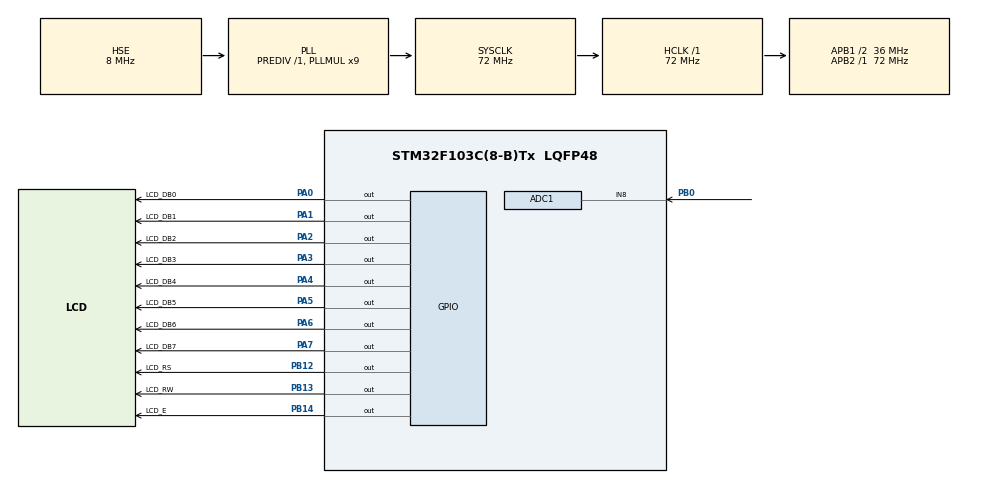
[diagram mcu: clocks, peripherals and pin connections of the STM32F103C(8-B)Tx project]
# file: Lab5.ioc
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ADC1.Channel-0\#ChannelRegularConversion=ADC_CHANNEL_8
ADC1.ContinuousConvMode=ENABLE
ADC1.NbrOfConversionFlag=1
ADC1.Rank-0\#ChannelRegularConversion=1
ADC1.SamplingTime-0\#ChannelRegularConversion=ADC_SAMPLETIME_1CYCLE_5
ADC1.master=1
Mcu.Family=STM32F1
Mcu.Name=STM32F103C(8-B)Tx
Mcu.Package=LQFP48
NVIC.PriorityGroup=NVIC_PRIORITYGROUP_4
PA0-WKUP.GPIO_Label=LCD_DB0
PA0-WKUP.GPIO_Speed=GPIO_SPEED_FREQ_MEDIUM
PA0-WKUP.Signal=GPIO_Output
PA1.GPIO_Label=LCD_DB1
PA1.GPIO_Speed=GPIO_SPEED_FREQ_MEDIUM
PA1.Signal=GPIO_Output
PA13.Mode=Serial_Wire
PA13.Signal=SYS_JTMS-SWDIO
PA14.Mode=Serial_Wire
PA14.Signal=SYS_JTCK-SWCLK
PA2.GPIO_Label=LCD_DB2
PA2.GPIO_Speed=GPIO_SPEED_FREQ_MEDIUM
PA2.Signal=GPIO_Output
PA3.GPIO_Label=LCD_DB3
PA3.GPIO_Speed=GPIO_SPEED_FREQ_MEDIUM
PA3.Signal=GPIO_Output
PA4.GPIO_Label=LCD_DB4
PA4.GPIO_Speed=GPIO_SPEED_FREQ_MEDIUM
PA4.Signal=GPIO_Output
PA5.GPIO_Label=LCD_DB5
PA5.GPIO_Speed=GPIO_SPEED_FREQ_MEDIUM
PA5.Signal=GPIO_Output
PA6.GPIO_Label=LCD_DB6
PA6.GPIO_Speed=GPIO_SPEED_FREQ_MEDIUM
PA6.Signal=GPIO_Output
PA7.GPIO_Label=LCD_DB7
PA7.GPIO_Speed=GPIO_SPEED_FREQ_MEDIUM
PA7.Signal=GPIO_Output
PB0.Signal=ADCx_IN8
PB12.GPIO_Label=LCD_RS
PB12.GPIO_Speed=GPIO_SPEED_FREQ_MEDIUM
PB12.Signal=GPIO_Output
PB13.GPIO_Label=LCD_RW
PB13.GPIO_Speed=GPIO_SPEED_FREQ_MEDIUM
PB13.Signal=GPIO_Output
PB14.GPIO_Label=LCD_E
PB14.GPIO_Speed=GPIO_SPEED_FREQ_MEDIUM
PB14.Signal=GPIO_Output
PD0-OSC_IN.Mode=HSE-External-Oscillator
PD0-OSC_IN.Signal=RCC_OSC_IN
PD1-OSC_OUT.Mode=HSE-External-Oscillator
PD1-OSC_OUT.Signal=RCC_OSC_OUT
ProjectManager.HeapSize=0x200
ProjectManager.StackSize=0x400
ProjectManager.TargetToolchain=Makefile
RCC.ADCPresc=RCC_ADCPCLK2_DIV6
RCC.AHBFreq_Value=72000000
RCC.APB1CLKDivider=RCC_HCLK_DIV2
RCC.APB1Freq_Value=36000000
RCC.APB1TimFreq_Value=72000000
RCC.APB2Freq_Value=72000000
RCC.APB2TimFreq_Value=72000000
RCC.HCLKFreq_Value=72000000
RCC.PLLMUL=RCC_PLL_MUL9
RCC.PLLSourceVirtual=RCC_PLLSOURCE_HSE
RCC.SYSCLKFreq_VALUE=72000000
RCC.SYSCLKSource=RCC_SYSCLKSOURCE_PLLCLK
RCC.USBFreq_Value=72000000
SH.ADCx_IN8.0=ADC1_IN8,IN8
board=custom

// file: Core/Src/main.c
/* USER CODE BEGIN Header */
/**
 ******************************************************************************
 * @file           : main.c
 * @brief          : Main program body
 ******************************************************************************
 * @attention
 *
 * Copyright (c) 2024 STMicroelectronics.
 * All rights reserved.
 *
 * This software is licensed under terms that can be found in the LICENSE file
 * in the root directory of this software component.
 * If no LICENSE file comes with this software, it is provided AS-IS.
 *
 ******************************************************************************
 */
/* USER CODE END Header */
#include "adc.h"
#include "gpio.h"
#include "main.h"

/* USER CODE BEGIN Includes */
#include "Delay.h"
#include "lcd1602.h"
/* USER CODE END Includes */

void SystemClock_Config(void);

int main(void) {

  /* MCU Configuration--------------------------------------------------------*/

  /* Reset of all peripherals, Initializes the Flash interface and the Systick.
   */
  HAL_Init();

  /* Configure the system clock */
  SystemClock_Config();

  /* Initialize all configured peripherals */
  MX_GPIO_Init();
  MX_ADC1_Init();
  /* USER CODE BEGIN 2 */

  LCD_init(); // BJ LCD initiate
  // uchar startStr2[] = "SJTU JI - LAB3";
  uchar Str1[] = {"voltage:"};
  uchar Space = ' '; // LCD显示‘：’
  uchar dot = '.';   // LCD显示".";
  uchar unit = 'v';  // LCD显示"v";
  uchar Num0 = '0';  // LCD显示数字“0”

  uint16_t AD_Value; // 保存AD采样得到的值
  float voltage;     // 保存浮点
  uint8_t vol0;
  uint8_t vol1;
  uint8_t vol2;
  uint8_t volt0;
  uint8_t volt1;
  uint8_t volt2;

  /* USER CODE END 2 */

  /* Infinite loop */
  while (1) {

    /* USER CODE BEGIN 3 */

    HAL_ADC_Start(&hadc1); // 启动ADC转换
    HAL_ADC_PollForConversion(
        &hadc1, 10); // 等待转换完成，第二个参数表示超时时间，单位ms.
    if (HAL_IS_BIT_SET(HAL_ADC_GetState(&hadc1), HAL_ADC_STATE_REG_EOC)) {
      AD_Value = HAL_ADC_GetValue(&hadc1); // 读取ADC转换数据，数据为12位
    }

    voltage =
        (float)AD_Value / 4095 * 3.3; // 将AD值线性变换到0~3.3的范围，表示电压

    volt0 = (uchar)((int)(voltage * 100) % 100); // 小数后面两位
    volt1 = (uchar)(voltage * 10) % 10;          // 小数后面第一位
    volt2 = (uchar)(volt0) % 10;                 // 小数后面第二位

    /*以下LCD显示电压AD采样值*/
    LCD_Display_String(0, 0, Str1); // 显示"voltage:"
    LCD_Display_Char(unit, 13, 0);  // 显示”v"
    LCD_Display_Char(Space, 8, 0);  // 显示”：“
    LCD_Display_Char(dot, 10, 0);   // 显示“.”

    vol0 = Num0 + (int)voltage; // 模拟电压的整数部分值
    vol1 = Num0 + volt1; // 模拟电压的小数后面第一位
    vol2 = Num0 + volt2; // 模拟电压的小数后面第二位

    LCD_Display_Char(vol0, 9, 0); // 显示电压值的整数部分
    LCD_Display_Char(vol1, 11, 0); // 显示电压值的小数第一位部分
    LCD_Display_Char(vol2, 12, 0); // 显示电压值的小数第二位部分

    Delay_ms(100);
  }
  /* USER CODE END 3 */
}

void SystemClock_Config(void) {
  RCC_OscInitTypeDef RCC_OscInitStruct = {0};
  RCC_ClkInitTypeDef RCC_ClkInitStruct = {0};
  RCC_PeriphCLKInitTypeDef PeriphClkInit = {0};

  /** Initializes the RCC Oscillators according to the specified parameters
   * in the RCC_OscInitTypeDef structure.
   */
  RCC_OscInitStruct.OscillatorType = RCC_OSCILLATORTYPE_HSE;
  RCC_OscInitStruct.HSEState = RCC_HSE_ON;
  RCC_OscInitStruct.HSEPredivValue = RCC_HSE_PREDIV_DIV1;
  RCC_OscInitStruct.HSIState = RCC_HSI_ON;
  RCC_OscInitStruct.PLL.PLLState = RCC_PLL_ON;
  RCC_OscInitStruct.PLL.PLLSource = RCC_PLLSOURCE_HSE;
  RCC_OscInitStruct.PLL.PLLMUL = RCC_PLL_MUL9;
  if (HAL_RCC_OscConfig(&RCC_OscInitStruct) != HAL_OK) {
    Error_Handler();
  }

  /** Initializes the CPU, AHB and APB buses clocks
   */
  RCC_ClkInitStruct.ClockType = RCC_CLOCKTYPE_HCLK | RCC_CLOCKTYPE_SYSCLK |
                                RCC_CLOCKTYPE_PCLK1 | RCC_CLOCKTYPE_PCLK2;
  RCC_ClkInitStruct.SYSCLKSource = RCC_SYSCLKSOURCE_PLLCLK;
  RCC_ClkInitStruct.AHBCLKDivider = RCC_SYSCLK_DIV1;
  RCC_ClkInitStruct.APB1CLKDivider = RCC_HCLK_DIV2;
  RCC_ClkInitStruct.APB2CLKDivider = RCC_HCLK_DIV1;

  if (HAL_RCC_ClockConfig(&RCC_ClkInitStruct, FLASH_LATENCY_2) != HAL_OK) {
    Error_Handler();
  }
  PeriphClkInit.PeriphClockSelection = RCC_PERIPHCLK_ADC;
  PeriphClkInit.AdcClockSelection = RCC_ADCPCLK2_DIV6;
  if (HAL_RCCEx_PeriphCLKConfig(&PeriphClkInit) != HAL_OK) {
    Error_Handler();
  }
}

void Error_Handler(void) {
  __disable_irq();
  while (1) {
  }
}

#ifdef USE_FULL_ASSERT
/**
 * @brief  Reports the name of the source file and the source line number
 *         where the assert_param error has occurred.
 * @param  file: pointer to the source file name
 * @param  line: assert_param error line source number
 * @retval None
 */
void assert_failed(uint8_t *file, uint32_t line) {
  /* USER CODE BEGIN 6 */
  /* User can add his own implementation to report the file name and line
     number, ex: printf("Wrong parameters value: file %s on line %d\r\n", file,
     line) */
  /* USER CODE END 6 */
}
#endif /* USE_FULL_ASSERT */
